One B-rep face of a CAD part: STEP entity #1045.
In plain terms, the cylindrical face has radius 13 mm (diameter 26 mm), a partial arc.
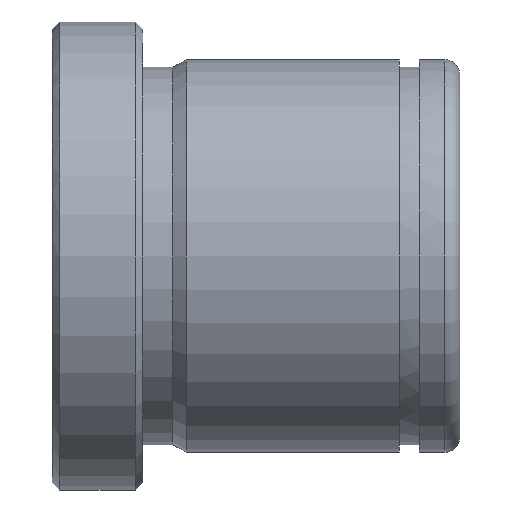
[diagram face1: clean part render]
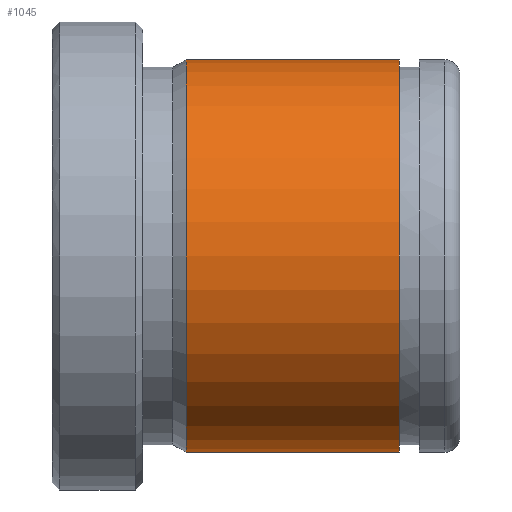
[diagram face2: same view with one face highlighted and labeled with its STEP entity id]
Its self-contained STEP definition (entity closure, numbers rounded to 3 decimals):
#851=CARTESIAN_POINT('Vertex',(8.866,0.,-13.)) ;
#858=CARTESIAN_POINT('Vertex',(8.866,0.,13.)) ;
#887=CARTESIAN_POINT('Axis2P3D Location',(8.866,0.,0.)) ;
#891=CARTESIAN_POINT('Vertex',(8.866,-13.,0.)) ;
#894=CARTESIAN_POINT('Axis2P3D Location',(8.866,0.,0.)) ;
#985=CARTESIAN_POINT('Line Origine',(54.,0.,13.)) ;
#989=CARTESIAN_POINT('Vertex',(23.,0.,13.)) ;
#1003=CARTESIAN_POINT('Vertex',(23.,0.,-13.)) ;
#1006=CARTESIAN_POINT('Line Origine',(54.,0.,-13.)) ;
#1020=CARTESIAN_POINT('Axis2P3D Location',(54.,0.,0.)) ;
#1025=CARTESIAN_POINT('Axis2P3D Location',(23.,0.,0.)) ;
#1029=CARTESIAN_POINT('Vertex',(23.,-13.,0.)) ;
#1032=CARTESIAN_POINT('Axis2P3D Location',(23.,0.,0.)) ;
#888=DIRECTION('Axis2P3D Direction',(1.,0.,-0.)) ;
#895=DIRECTION('Axis2P3D Direction',(1.,0.,-0.)) ;
#986=DIRECTION('Vector Direction',(-1.,0.,0.)) ;
#1007=DIRECTION('Vector Direction',(-1.,0.,0.)) ;
#1021=DIRECTION('Axis2P3D Direction',(-1.,-0.,-0.)) ;
#1022=DIRECTION('Axis2P3D XDirection',(0.,0.,-1.)) ;
#1026=DIRECTION('Axis2P3D Direction',(-1.,-0.,-0.)) ;
#1033=DIRECTION('Axis2P3D Direction',(-1.,-0.,-0.)) ;
#889=AXIS2_PLACEMENT_3D('Circle Axis2P3D',#887,#888,$) ;
#896=AXIS2_PLACEMENT_3D('Circle Axis2P3D',#894,#895,$) ;
#1023=AXIS2_PLACEMENT_3D('Cylinder Axis2P3D',#1020,#1021,#1022) ;
#1027=AXIS2_PLACEMENT_3D('Circle Axis2P3D',#1025,#1026,$) ;
#1034=AXIS2_PLACEMENT_3D('Circle Axis2P3D',#1032,#1033,$) ;
#1038=ORIENTED_EDGE('',*,*,#1010,.T.) ;
#1039=ORIENTED_EDGE('',*,*,#1031,.F.) ;
#1040=ORIENTED_EDGE('',*,*,#1036,.F.) ;
#1041=ORIENTED_EDGE('',*,*,#991,.T.) ;
#1042=ORIENTED_EDGE('',*,*,#898,.T.) ;
#1043=ORIENTED_EDGE('',*,*,#893,.T.) ;
#987=VECTOR('Line Direction',#986,1.) ;
#1008=VECTOR('Line Direction',#1007,1.) ;
#1045=ADVANCED_FACE('553-20X27',(#1044),#1024,.T.) ;
#890=CIRCLE('generated circle',#889,13.) ;
#897=CIRCLE('generated circle',#896,13.) ;
#1028=CIRCLE('generated circle',#1027,13.) ;
#1035=CIRCLE('generated circle',#1034,13.) ;
#1024=CYLINDRICAL_SURFACE('generated cylinder',#1023,13.) ;
#893=EDGE_CURVE('',#892,#852,#890,.T.) ;
#898=EDGE_CURVE('',#859,#892,#897,.T.) ;
#991=EDGE_CURVE('',#990,#859,#988,.T.) ;
#1010=EDGE_CURVE('',#852,#1004,#1009,.F.) ;
#1031=EDGE_CURVE('',#1030,#1004,#1028,.F.) ;
#1036=EDGE_CURVE('',#990,#1030,#1035,.F.) ;
#1037=EDGE_LOOP('',(#1038,#1039,#1040,#1041,#1042,#1043)) ;
#1044=FACE_OUTER_BOUND('',#1037,.T.) ;
#988=LINE('Line',#985,#987) ;
#1009=LINE('Line',#1006,#1008) ;
#852=VERTEX_POINT('',#851) ;
#859=VERTEX_POINT('',#858) ;
#892=VERTEX_POINT('',#891) ;
#990=VERTEX_POINT('',#989) ;
#1004=VERTEX_POINT('',#1003) ;
#1030=VERTEX_POINT('',#1029) ;
